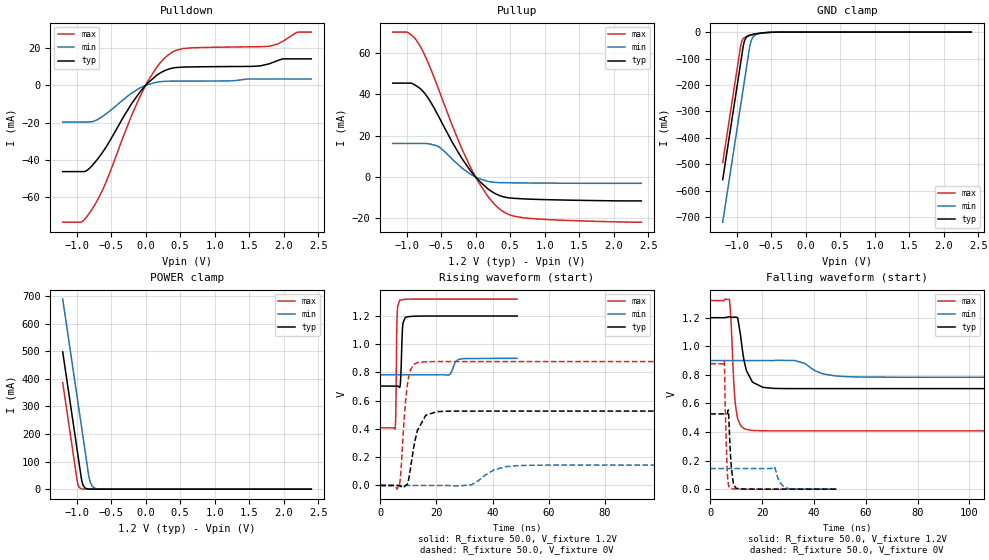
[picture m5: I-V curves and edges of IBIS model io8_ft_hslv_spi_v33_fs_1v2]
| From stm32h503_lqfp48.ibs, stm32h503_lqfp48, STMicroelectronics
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[Model]   io8_ft_hslv_spi_v33_fs_1v2
Model_type I/O
Polarity   Non-Inverting
Enable   Active-Low
| CAP_THRESHOLD on pad IOFT is "UDTCAPC" :
| Rising=20.0% of vddiom   Falling=80.0% of vddiom
| C_comp min and max val. don't necessarily correlate with the min and max pvt
| but are the smallest and greatest pad capacitance found.
| var   typ   min   max
C_comp   3.39570pF  3.37235pF  3.42680pF
|C_comp_pullup   2.09365pF  2.00520pF  1.90825pF
|C_comp_pulldown   1.30205pF  1.36715pF  1.51855pF
Vinl = 270.0mV
Vinh = 924.0mV
Vmeas = 600.0mV   | Reference voltage for timing measurements
Cref  = 50.0pF   | Timing specification test load capacitance value
Rref  = 100.0MOhm   | Timing specification test load resistance value
Vref  = 600.0mV   | Timing specification test load voltage
[Model Spec]
| TIME_THRESHOLD on pin ZIV33M is "CMOS" :
| Rising=40.0% of vddiom   Falling=60.0% of vddiom
Vinl 437.80000mV 335.80000mV 479.80000mV
Vinh 728.20000mV 529.20000mV 807.20000mV
| variable   typ   min   max
[Temperature Range] 25.0 125.0 -40.0
| variable   typ   min   max
[Voltage Range] 1.2V 900.0mV 1.32V
| variable   typ   min   max
[POWER Clamp Reference] 1.2V 900.0mV 1.32V
| variable   typ   min   max
[GND Clamp Reference] 0V 0V 0V
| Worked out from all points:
|   slope of the pulldown table from 0 to 0.18 V, typ, clamps not added: 30.6 ohm
|   slope of the pullup table from 0 to 0.18 V, typ, clamps not added: 31.3 ohm
|   GND clamp passes 1 mA (typ) near -0.52 V on its own axis
|   POWER clamp passes 1 mA (typ) near -0.84 V on its own axis
|   rising waveform, R_fixture 50.0, V_fixture 1.2V: 20-80 % time 520ps typ, 1.45ns min, 319ps max; typ from 0.704 V to 1.2 V
|   falling waveform, R_fixture 50.0, V_fixture 1.2V: 20-80 % time 3.24ns typ, 7.01ns min, 1.6ns max; typ from 1.2 V to 0.704 V
|   rising waveform, R_fixture 50.0, V_fixture 0V: 20-80 % time 3.48ns typ, 6.93ns min, 1.98ns max; typ from 0 V to 0.527 V
|   falling waveform, R_fixture 50.0, V_fixture 0V: 20-80 % time 1.12ns typ, 2.21ns min, 804ps max; typ from 0.527 V to 0 V
[POWER Clamp]
-1.2V     497.8mA    689.2mA    386.5mA
-990mV    140.8mA    332.2mA    29.53mA
-980mV    123.8mA    315.2mA    17.95mA
-960mV    89.81mA    281.2mA    6.634mA
-930mV    38.81mA    230.2mA    1.49mA
-900mV    12.07mA    179.2mA    334.8uA
-870mV    3.756mA    128.2mA    75.22uA
-820mV    536.4uA    44.98mA    6.246uA
-790mV    166.9uA    18.76mA    1.403uA
-750mV    35.18uA    5.846mA    191.8nA
-590mV    70.08nA    55uA       163.4pA
2.4V      0A         0A         0A
[GND Clamp]
-1.2V     -558.2mA   -719mA     -494.1mA
-940mV    -116.2mA   -277mA     -52.06mA
-930mV    -99.19mA   -260mA     -39.94mA
-900mV    -49.1mA    -209mA     -23.76mA
-880mV    -30.14mA   -175mA     -19.6mA
-850mV    -17.82mA   -124mA     -16.09mA
-810mV    -11.73mA   -56.78mA   -12.91mA
-780mV    -9.444mA   -28.21mA   -10.92mA
-740mV    -7.291mA   -13.16mA   -8.574mA
-640mV    -3.573mA   -4.171mA   -3.954mA
-380mV    -61.75uA   -230.3uA   -20.32uA
2.4V      3.863nA    718.6nA    150.6pA
| variable   typ   min   max
[Pullup Reference] 1.2V 900.0mV 1.32V
| variable   typ   min   max
[Pulldown Reference] 0V 0V 0V
[Pullup]
-1.2V     45.41mA    16.23mA    70.08mA
-990mV    45.41mA    16.23mA    70.08mA
-820mV    43.23mA    16.23mA    64.23mA
-700mV    38.81mA    16.16mA    56.25mA
-540mV    29.64mA    14.73mA    42.86mA
-330mV    16.36mA    8.38mA     24.24mA
-80mV     3.305mA    1.499mA    5.124mA
170mV     -5.505mA   -2.032mA   -9.004mA
360mV     -9.115mA   -2.712mA   -15.76mA
540mV     -10.25mA   -2.811mA   -18.8mA
790mV     -10.7mA    -2.892mA   -20.02mA
2.4V      -11.55mA   -3.057mA   -21.84mA
[Pulldown]
-1.2V     -46.17mA   -19.62mA   -73.27mA
-930mV    -46.17mA   -19.62mA   -73.18mA
-770mV    -42.8mA    -19.41mA   -66.04mA
-570mV    -32.88mA   -15.18mA   -51.58mA
-80mV     -3.488mA   -1.363mA   -5.887mA
160mV     5.368mA    1.686mA    9.621mA
340mV     8.782mA    2.251mA    16.66mA
540mV     9.805mA    2.305mA    19.74mA
1.79V     11.53mA    3.428mA    20.94mA
1.98V     14.11mA    3.428mA    23.43mA
2.2V      14.2mA     3.428mA    28.44mA
2.4V      14.2mA     3.428mA    28.54mA
[Ramp]
dV/dt_r 315.97829mV/3.11017ns 86.46871mV/6.5409ns 526.34887mV/1.98266ns
dV/dt_f 297.80503mV/2.96734ns 69.92309mV/6.87924ns 547.13925mV/1.59983ns
R_load = 50.0
| Removed startup time: 0s 0s 0s  .
| Removed end time: 48.75ns.
[Rising Waveform]
R_fixture   = 50.0
V_fixture   = 1.2V
V_fixture_min = 900.0mV
V_fixture_max = 1.32V
0s        703.7mV    783.5mV    408.1mV
5.3ns     703.7mV    783.5mV    404.1mV
5.55ns    703.8mV    783.5mV    536.4mV
5.8ns     703.8mV    783.5mV    1.003V
6ns       703.9mV    783.5mV    1.205V
6.9ns     694.2mV    783.5mV    1.312V
7.3ns     771.8mV    783.5mV    1.312V
8ns       1.133V     783.5mV    1.316V
8.95ns    1.191V     783.5mV    1.318V
48.75ns   1.2V       899.9mV    1.32V
| Removed startup time: 0s 0s 0s  .
| Removed end time: 198.75ns.
[Falling Waveform]
R_fixture   = 50.0
V_fixture   = 1.2V
V_fixture_min = 900.0mV
V_fixture_max = 1.32V
0s        1.2V       900mV      1.32V
7.4ns     1.207V     900mV      1.324V
9.1ns     1.204V     900mV      736.5mV
9.7ns     1.204V     900mV      591.1mV
10.65ns   1.192V     900mV      488.5mV
13.95ns   829.2mV    900mV      417.5mV
16.25ns   749.4mV    900mV      410.7mV
24.35ns   705.5mV    899.6mV    408.1mV
52.75ns   703.7mV    787.3mV    408.1mV
198.8ns   703.7mV    783.5mV    408.1mV
| Removed startup time: 0s 0s 0s  .
| Removed end time: 198.7ns.
[Rising Waveform]
R_fixture   = 50.0
V_fixture   = 0V
V_fixture_min = 0V
V_fixture_max = 0V
0s        198.1nV    697.3nV    135nV
6.8ns     -866.9uV   704.3nV    6.54mV
7.3ns     -7.541mV   702.4nV    86.73mV
8.8ns     -3.423mV   691.5nV    545mV
9.8ns     18.47mV    679.1nV    733.6mV
13.2ns    387.9mV    568.3nV    870mV
20.3ns    523.1mV    793.1nV    877.1mV
32.5ns    526.5mV    4.756mV    877.2mV
48.7ns    526.5mV    140.1mV    877.2mV
198.7ns   526.6mV    144.1mV    877.2mV
| Removed startup time: 0s 0s 0s  .
| Removed end time: 48.75ns.
[Falling Waveform]
R_fixture   = 50.0
V_fixture   = 0V
V_fixture_min = 0V
V_fixture_max = 0V
0s        526.6mV    144.1mV    877.3mV
5.4ns     526.7mV    144.1mV    896.5mV
5.85ns    526.7mV    144.1mV    509.4mV
6.55ns    528.8mV    144.1mV    132.1mV
7.05ns    538.4mV    144.1mV    28.87mV
7.7ns     270.8mV    144.1mV    6.568mV
8.95ns    34.17mV    144.1mV    1.678mV
9.95ns    6.36mV     144.1mV    806.1uV
24.7ns    9.7uV      155.5mV    742.8nV
48.75ns   60.78nV    149.7uV    31.8nV
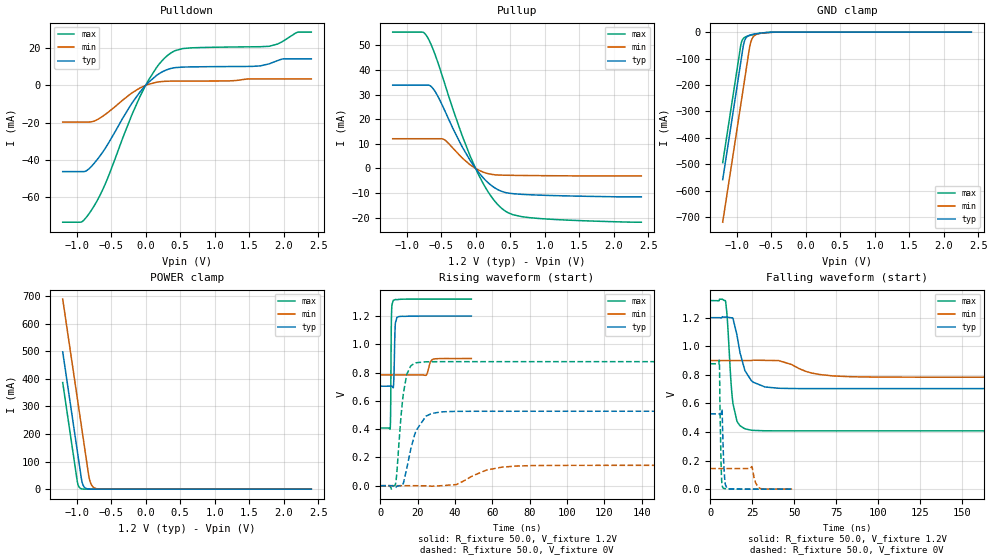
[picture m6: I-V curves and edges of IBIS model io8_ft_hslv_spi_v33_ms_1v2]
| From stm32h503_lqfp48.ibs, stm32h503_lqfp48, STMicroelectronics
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[Model]   io8_ft_hslv_spi_v33_ms_1v2
Model_type I/O
Polarity   Non-Inverting
Enable   Active-Low
| CAP_THRESHOLD on pad IOFT is "UDTCAPC" :
| Rising=20.0% of vddiom   Falling=80.0% of vddiom
| C_comp min and max val. don't necessarily correlate with the min and max pvt
| but are the smallest and greatest pad capacitance found.
| var   typ   min   max
C_comp   3.39570pF  3.37230pF  3.42685pF
|C_comp_pullup   2.09375pF  2.00530pF  1.90840pF
|C_comp_pulldown   1.30195pF  1.36700pF  1.51845pF
Vinl = 270.0mV
Vinh = 924.0mV
Vmeas = 600.0mV   | Reference voltage for timing measurements
Cref  = 50.0pF   | Timing specification test load capacitance value
Rref  = 100.0MOhm   | Timing specification test load resistance value
Vref  = 600.0mV   | Timing specification test load voltage
[Model Spec]
| TIME_THRESHOLD on pin ZIV33M is "CMOS" :
| Rising=40.0% of vddiom   Falling=60.0% of vddiom
Vinl 437.80000mV 335.80000mV 479.80000mV
Vinh 728.20000mV 529.20000mV 807.20000mV
| variable   typ   min   max
[Temperature Range] 25.0 125.0 -40.0
| variable   typ   min   max
[Voltage Range] 1.2V 900.0mV 1.32V
| variable   typ   min   max
[POWER Clamp Reference] 1.2V 900.0mV 1.32V
| variable   typ   min   max
[GND Clamp Reference] 0V 0V 0V
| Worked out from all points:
|   slope of the pulldown table from 0 to 0.18 V, typ, clamps not added: 30.6 ohm
|   slope of the pullup table from 0 to 0.18 V, typ, clamps not added: 31.2 ohm
|   GND clamp passes 1 mA (typ) near -0.52 V on its own axis
|   POWER clamp passes 1 mA (typ) near -0.84 V on its own axis
|   rising waveform, R_fixture 50.0, V_fixture 1.2V: 20-80 % time 520ps typ, 1.44ns min, 319ps max; typ from 0.704 V to 1.2 V
|   falling waveform, R_fixture 50.0, V_fixture 1.2V: 20-80 % time 6.64ns typ, 15.8ns min, 3.24ns max; typ from 1.2 V to 0.704 V
|   rising waveform, R_fixture 50.0, V_fixture 0V: 20-80 % time 6.92ns typ, 14.9ns min, 3.69ns max; typ from 0 V to 0.527 V
|   falling waveform, R_fixture 50.0, V_fixture 0V: 20-80 % time 1.07ns typ, 2.17ns min, 800ps max; typ from 0.527 V to 0 V
[POWER Clamp]
-1.2V     497.8mA    689.2mA    386.5mA
-990mV    140.8mA    332.2mA    29.53mA
-980mV    123.8mA    315.2mA    17.95mA
-960mV    89.81mA    281.2mA    6.634mA
-930mV    38.81mA    230.2mA    1.49mA
-900mV    12.07mA    179.2mA    334.8uA
-870mV    3.756mA    128.2mA    75.22uA
-820mV    536.4uA    44.98mA    6.246uA
-790mV    166.9uA    18.76mA    1.403uA
-750mV    35.18uA    5.846mA    191.8nA
-590mV    70.08nA    55uA       163.4pA
2.4V      0A         0A         0A
[GND Clamp]
-1.2V     -558.2mA   -719mA     -494.1mA
-940mV    -116.2mA   -277mA     -52.06mA
-930mV    -99.19mA   -260mA     -39.94mA
-900mV    -49.1mA    -209mA     -23.76mA
-880mV    -30.14mA   -175mA     -19.6mA
-850mV    -17.82mA   -124mA     -16.09mA
-810mV    -11.73mA   -56.78mA   -12.91mA
-780mV    -9.444mA   -28.21mA   -10.92mA
-740mV    -7.291mA   -13.16mA   -8.574mA
-640mV    -3.573mA   -4.171mA   -3.954mA
-380mV    -61.75uA   -230.3uA   -20.32uA
2.4V      3.863nA    718.6nA    150.6pA
| variable   typ   min   max
[Pullup Reference] 1.2V 900.0mV 1.32V
| variable   typ   min   max
[Pulldown Reference] 0V 0V 0V
[Pullup]
-1.2V     33.83mA    12.07mA    55.39mA
-770mV    33.83mA    12.07mA    55.39mA
-700mV    33.83mA    12.07mA    53.47mA
-600mV    31.84mA    12.07mA    47.27mA
-450mV    23.73mA    11.63mA    34.72mA
-200mV    9.076mA    4.405mA    13.76mA
0V        5.98pA     656pA      2.91pA
200mV     -6.256mA   -2.236mA   -10.31mA
400mV     -9.528mA   -2.741mA   -16.71mA
540mV     -10.25mA   -2.81mA    -18.8mA
790mV     -10.7mA    -2.891mA   -20.02mA
2.4V      -11.55mA   -3.057mA   -21.84mA
[Pulldown]
-1.2V     -46.17mA   -19.62mA   -73.27mA
-930mV    -46.17mA   -19.62mA   -73.18mA
-770mV    -42.8mA    -19.41mA   -66.04mA
-570mV    -32.88mA   -15.18mA   -51.58mA
-80mV     -3.488mA   -1.363mA   -5.887mA
160mV     5.368mA    1.686mA    9.621mA
340mV     8.782mA    2.251mA    16.66mA
540mV     9.805mA    2.305mA    19.74mA
1.79V     11.53mA    3.428mA    20.94mA
1.98V     14.11mA    3.428mA    23.43mA
2.2V      14.2mA     3.428mA    28.44mA
2.4V      14.2mA     3.428mA    28.54mA
[Ramp]
dV/dt_r 315.9766mV/6.30353ns 86.46mV/14.30989ns 526.3497mV/3.54733ns
dV/dt_f 297.8051mV/6.16485ns 69.92056mV/15.0681ns 547.13928mV/3.15941ns
R_load = 50.0
| Removed startup time: 0s 0s 0s  .
| Removed end time: 48.75ns.
[Rising Waveform]
R_fixture   = 50.0
V_fixture   = 1.2V
V_fixture_min = 900.0mV
V_fixture_max = 1.32V
0s        703.7mV    783.5mV    408.1mV
5.3ns     703.7mV    783.5mV    402.5mV
5.55ns    703.7mV    783.5mV    531.4mV
5.85ns    703.7mV    783.5mV    1.067V
6ns       703.8mV    783.5mV    1.205V
6.9ns     692.1mV    783.5mV    1.31V
7.3ns     769.4mV    783.5mV    1.313V
8ns       1.132V     783.5mV    1.316V
8.95ns    1.191V     783.5mV    1.316V
48.75ns   1.2V       899.5mV    1.32V
| Removed startup time: 0s 0s 0s  .
| Removed end time: 398.75ns.
[Falling Waveform]
R_fixture   = 50.0
V_fixture   = 1.2V
V_fixture_min = 900.0mV
V_fixture_max = 1.32V
0s        1.2V       900mV      1.32V
9.05ns    1.204V     900mV      1.317V
10.1ns    1.204V     900mV      1.198V
12.2ns    1.2V       900mV      772.2mV
13.5ns    1.195V     900mV      599.4mV
16.3ns    1.05V      900mV      466.6mV
20.6ns    830mV      900mV      422.2mV
24.4ns    760mV      899.6mV    412.6mV
85.1ns    703.7mV    786.5mV    408.1mV
398.8ns   703.7mV    783.5mV    408.1mV
| Removed startup time: 0s 0s 0s  .
| Removed end time: 398.7ns.
[Rising Waveform]
R_fixture   = 50.0
V_fixture   = 0V
V_fixture_min = 0V
V_fixture_max = 0V
0s        188.3nV    695.1nV    128.8nV
8.1ns     -14.09mV   699.3nV    9.156mV
12.4ns    19.26mV    622.9nV    656mV
14.2ns    123.6mV    487.8nV    788.6mV
19.2ns    390.2mV    758.2nV    869.5mV
27.4ns    510.4mV    -3.642mV   876.9mV
40.7ns    525.8mV    8.138mV    877.1mV
57ns      526.4mV    110.7mV    877.2mV
73.2ns    526.5mV    139.4mV    877.2mV
398.7ns   526.6mV    144.1mV    877.2mV
| Removed startup time: 0s 0s 0s  .
| Removed end time: 48.75ns.
[Falling Waveform]
R_fixture   = 50.0
V_fixture   = 0V
V_fixture_min = 0V
V_fixture_max = 0V
0s        526.6mV    144.1mV    877.3mV
5.4ns     526.7mV    144.1mV    900.4mV
5.85ns    526.7mV    144.1mV    516mV
6.55ns    529.1mV    144.1mV    131.2mV
7.05ns    545.1mV    144.1mV    27.43mV
7.7ns     275.3mV    144.1mV    7.634mV
8.55ns    78.95mV    144.1mV    4.106mV
9.95ns    5.762mV    144.1mV    2.501mV
24.7ns    131.6uV    158.5mV    14.21uV
48.75ns   871.1nV    485.8uV    36.49nV
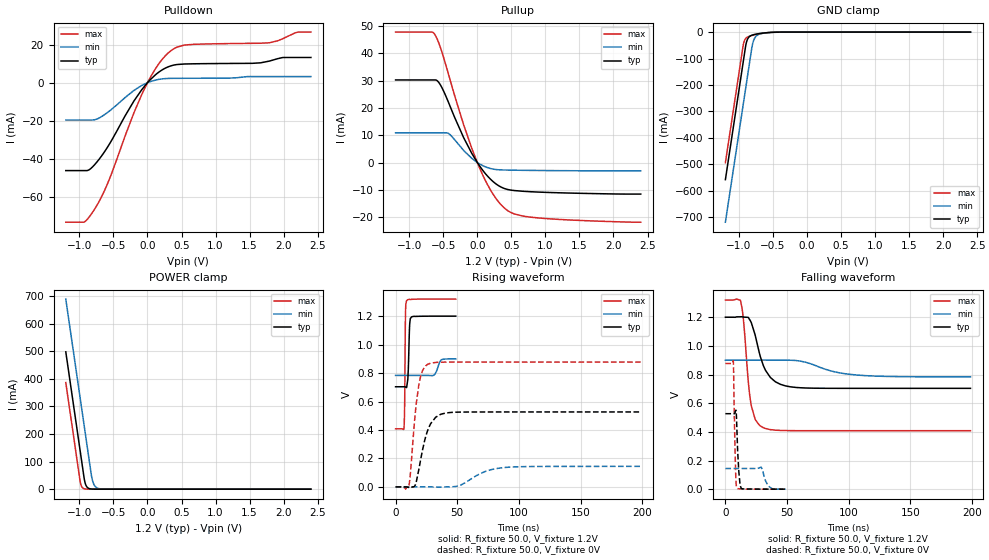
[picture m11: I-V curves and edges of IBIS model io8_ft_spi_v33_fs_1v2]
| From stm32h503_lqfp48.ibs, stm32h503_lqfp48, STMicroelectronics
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[Model]   io8_ft_spi_v33_fs_1v2
Model_type I/O
Polarity   Non-Inverting
Enable   Active-Low
| CAP_THRESHOLD on pad IOFT is "UDTCAPC" :
| Rising=20.0% of vddiom   Falling=80.0% of vddiom
| C_comp min and max val. don't necessarily correlate with the min and max pvt
| but are the smallest and greatest pad capacitance found.
| var   typ   min   max
C_comp   3.39520pF  3.36980pF  3.42665pF
|C_comp_pullup   2.08475pF  1.99620pF  1.90095pF
|C_comp_pulldown   1.31045pF  1.37360pF  1.52570pF
Vinl = 270.0mV
Vinh = 924.0mV
Vmeas = 600.0mV   | Reference voltage for timing measurements
Cref  = 50.0pF   | Timing specification test load capacitance value
Rref  = 100.0MOhm   | Timing specification test load resistance value
Vref  = 600.0mV   | Timing specification test load voltage
[Model Spec]
| TIME_THRESHOLD on pin ZIV33M is "CMOS" :
| Rising=40.0% of vddiom   Falling=60.0% of vddiom
Vinl 437.80000mV 335.80000mV 479.80000mV
Vinh 728.20000mV 529.20000mV 807.20000mV
| variable   typ   min   max
[Temperature Range] 25.0 125.0 -40.0
| variable   typ   min   max
[Voltage Range] 1.2V 900.0mV 1.32V
| variable   typ   min   max
[POWER Clamp Reference] 1.2V 900.0mV 1.32V
| variable   typ   min   max
[GND Clamp Reference] 0V 0V 0V
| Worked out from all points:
|   slope of the pulldown table from 0 to 0.18 V, typ, clamps not added: 30.6 ohm
|   slope of the pullup table from 0 to 0.18 V, typ, clamps not added: 31.2 ohm
|   GND clamp passes 1 mA (typ) near -0.52 V on its own axis
|   POWER clamp passes 1 mA (typ) near -0.84 V on its own axis
|   rising waveform, R_fixture 50.0, V_fixture 1.2V: 20-80 % time 1.03ns typ, 2.95ns min, 542ps max; typ from 0.704 V to 1.2 V
|   falling waveform, R_fixture 50.0, V_fixture 1.2V: 20-80 % time 11.4ns typ, 27.5ns min, 5.74ns max; typ from 1.2 V to 0.704 V
|   rising waveform, R_fixture 50.0, V_fixture 0V: 20-80 % time 8.75ns typ, 18.9ns min, 5.83ns max; typ from 0 V to 0.527 V
|   falling waveform, R_fixture 50.0, V_fixture 0V: 20-80 % time 1.76ns typ, 3.89ns min, 1.26ns max; typ from 0.527 V to 0 V
[POWER Clamp]
-1.2V     497.8mA    689.2mA    386.5mA
-990mV    140.8mA    332.2mA    29.53mA
-980mV    123.8mA    315.2mA    17.95mA
-960mV    89.81mA    281.2mA    6.634mA
-930mV    38.81mA    230.2mA    1.49mA
-900mV    12.07mA    179.2mA    334.8uA
-870mV    3.756mA    128.2mA    75.22uA
-820mV    536.4uA    44.98mA    6.246uA
-790mV    166.9uA    18.76mA    1.403uA
-750mV    35.18uA    5.846mA    191.8nA
-590mV    70.09nA    55uA       165.5pA
2.4V      0A         0A         0A
[GND Clamp]
-1.2V     -558.2mA   -719mA     -494.1mA
-940mV    -116.2mA   -277mA     -52.06mA
-930mV    -99.19mA   -260mA     -39.94mA
-900mV    -49.1mA    -209mA     -23.76mA
-880mV    -30.14mA   -175mA     -19.6mA
-850mV    -17.82mA   -124mA     -16.09mA
-810mV    -11.73mA   -56.78mA   -12.91mA
-780mV    -9.444mA   -28.21mA   -10.92mA
-740mV    -7.291mA   -13.16mA   -8.574mA
-640mV    -3.573mA   -4.171mA   -3.954mA
-380mV    -61.75uA   -230.3uA   -20.32uA
2.4V      3.863nA    718.4nA    150.6pA
| variable   typ   min   max
[Pullup Reference] 1.2V 900.0mV 1.32V
| variable   typ   min   max
[Pulldown Reference] 0V 0V 0V
[Pullup]
-1.2V     30.2mA     10.86mA    47.72mA
-660mV    30.2mA     10.86mA    47.71mA
-620mV    30.2mA     10.86mA    46.69mA
-540mV    28.32mA    10.86mA    41.96mA
-420mV    21.81mA    10.57mA    32.02mA
-200mV    9.076mA    4.404mA    13.76mA
0V        5.98pA     656pA      2.91pA
220mV     -6.72mA    -2.348mA   -11.13mA
420mV     -9.693mA   -2.753mA   -17.12mA
540mV     -10.25mA   -2.811mA   -18.8mA
900mV     -10.82mA   -2.919mA   -20.3mA
2.4V      -11.55mA   -3.057mA   -21.84mA
[Pulldown]
-1.2V     -46.17mA   -19.62mA   -73.27mA
-930mV    -46.17mA   -19.62mA   -73.18mA
-770mV    -42.8mA    -19.41mA   -66.04mA
-570mV    -32.88mA   -15.18mA   -51.58mA
-200mV    -9.658mA   -4.083mA   -15.89mA
-80mV     -3.488mA   -1.363mA   -5.887mA
120mV     4.232mA    1.387mA    7.501mA
340mV     8.782mA    2.251mA    16.66mA
540mV     9.805mA    2.305mA    19.74mA
1.79V     11.33mA    3.206mA    20.93mA
2.2V      13.23mA    3.206mA    26.48mA
2.4V      13.23mA    3.206mA    26.56mA
[Ramp]
dV/dt_r 315.94699mV/8.63249ns 86.40379mV/18.62437ns 526.33866mV/5.7566ns
dV/dt_f 297.80515mV/10.97974ns 69.86081mV/27.41264ns 547.1393mV/5.72596ns
R_load = 50.0
| Removed startup time: 0s 0s 0s  .
| Removed end time: 48.75ns.
[Rising Waveform]
R_fixture   = 50.0
V_fixture   = 1.2V
V_fixture_min = 900.0mV
V_fixture_max = 1.32V
0s        703.7mV    783.5mV    408.1mV
6.85ns    703.8mV    783.5mV    419.2mV
7.35ns    703.8mV    783.5mV    580.7mV
8.05ns    701.8mV    783.5mV    1.221V
8.95ns    697.9mV    783.5mV    1.31V
9.95ns    759.1mV    783.5mV    1.316V
11.25ns   1.11V      783.5mV    1.318V
11.95ns   1.183V     783.5mV    1.317V
30.85ns   1.2V       784mV      1.32V
48.75ns   1.2V       899.4mV    1.32V
| Removed startup time: 0s 0s 0s  .
| Removed end time: 198.75ns.
[Falling Waveform]
R_fixture   = 50.0
V_fixture   = 1.2V
V_fixture_min = 900.0mV
V_fixture_max = 1.32V
0s        1.2V       900mV      1.32V
12.2ns    1.203V     900mV      1.317V
14.6ns    1.201V     900mV      1.184V
18.75ns   1.196V     900mV      734.7mV
21.05ns   1.161V     900mV      580.2mV
30.85ns   860.9mV    901.2mV    428.7mV
40.55ns   749.4mV    900.9mV    411.8mV
56.8ns    710.3mV    898.3mV    408.3mV
105.5ns   703.7mV    797.4mV    408.1mV
198.8ns   703.7mV    783.6mV    408.1mV
| Removed startup time: 0s 0s 0s  .
| Removed end time: 198.7ns.
[Rising Waveform]
R_fixture   = 50.0
V_fixture   = 0V
V_fixture_min = 0V
V_fixture_max = 0V
0s        198.4nV    700.8nV    136.1nV
10.8ns    -4.237mV   698nV      10.63mV
15.8ns    10.14mV    944.2nV    503.2mV
18.9ns    124.3mV    945.6nV    721.1mV
21.8ns    257.5mV    76.39nV    816.8mV
26.5ns    408.2mV    39.29uV    863.3mV
32.5ns    489.5mV    -1.143mV   874.7mV
44.6ns    523mV      133.9uV    877mV
85.2ns    526.4mV    133.2mV    877.2mV
198.7ns   526.6mV    144mV      877.2mV
| Removed startup time: 0s 0s 0s  .
| Removed end time: 48.75ns.
[Falling Waveform]
R_fixture   = 50.0
V_fixture   = 0V
V_fixture_min = 0V
V_fixture_max = 0V
0s        526.7mV    144.2mV    877.3mV
6.4ns     526.4mV    144.2mV    893.8mV
7.95ns    536.7mV    144.2mV    228.3mV
8.7ns     544.7mV    144.2mV    41.58mV
9.35ns    411.8mV    144.2mV    8.883mV
10.95ns   116.7mV    144.2mV    2.415mV
12.95ns   4.583mV    144.2mV    1.802mV
28.9ns    287.3uV    153.5mV    62.31uV
35.85ns   122.9uV    15.13mV    17.65uV
48.75ns   25.84uV    364.1uV    1.61uV
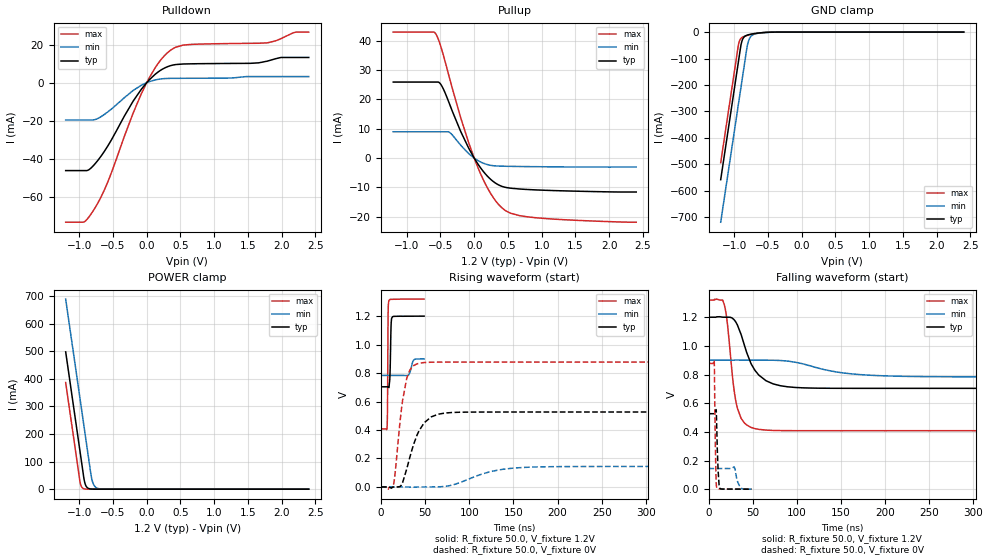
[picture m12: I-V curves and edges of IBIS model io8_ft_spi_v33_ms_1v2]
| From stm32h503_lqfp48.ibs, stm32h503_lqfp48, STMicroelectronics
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[Model]   io8_ft_spi_v33_ms_1v2
Model_type I/O
Polarity   Non-Inverting
Enable   Active-Low
| CAP_THRESHOLD on pad IOFT is "UDTCAPC" :
| Rising=20.0% of vddiom   Falling=80.0% of vddiom
| C_comp min and max val. don't necessarily correlate with the min and max pvt
| but are the smallest and greatest pad capacitance found.
| var   typ   min   max
C_comp   3.39520pF  3.36985pF  3.42675pF
|C_comp_pullup   2.08500pF  1.99655pF  1.90125pF
|C_comp_pulldown   1.31020pF  1.37330pF  1.52550pF
Vinl = 270.0mV
Vinh = 924.0mV
Vmeas = 600.0mV   | Reference voltage for timing measurements
Cref  = 50.0pF   | Timing specification test load capacitance value
Rref  = 100.0MOhm   | Timing specification test load resistance value
Vref  = 600.0mV   | Timing specification test load voltage
[Model Spec]
| TIME_THRESHOLD on pin ZIV33M is "CMOS" :
| Rising=40.0% of vddiom   Falling=60.0% of vddiom
Vinl 437.80000mV 335.80000mV 479.80000mV
Vinh 728.20000mV 529.20000mV 807.20000mV
| variable   typ   min   max
[Temperature Range] 25.0 125.0 -40.0
| variable   typ   min   max
[Voltage Range] 1.2V 900.0mV 1.32V
| variable   typ   min   max
[POWER Clamp Reference] 1.2V 900.0mV 1.32V
| variable   typ   min   max
[GND Clamp Reference] 0V 0V 0V
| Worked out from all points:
|   slope of the pulldown table from 0 to 0.18 V, typ, clamps not added: 30.6 ohm
|   slope of the pullup table from 0 to 0.18 V, typ, clamps not added: 31.2 ohm
|   GND clamp passes 1 mA (typ) near -0.52 V on its own axis
|   POWER clamp passes 1 mA (typ) near -0.84 V on its own axis
|   rising waveform, R_fixture 50.0, V_fixture 1.2V: 20-80 % time 1.02ns typ, 2.94ns min, 538ps max; typ from 0.704 V to 1.2 V
|   falling waveform, R_fixture 50.0, V_fixture 1.2V: 20-80 % time 20.5ns typ, 53.4ns min, 10.1ns max; typ from 1.2 V to 0.704 V
|   rising waveform, R_fixture 50.0, V_fixture 0V: 20-80 % time 17.7ns typ, 41.3ns min, 10.1ns max; typ from 0 V to 0.527 V
|   falling waveform, R_fixture 50.0, V_fixture 0V: 20-80 % time 1.78ns typ, 3.91ns min, 1.26ns max; typ from 0.527 V to 0 V
[POWER Clamp]
-1.2V     497.8mA    689.2mA    386.5mA
-990mV    140.8mA    332.2mA    29.53mA
-980mV    123.8mA    315.2mA    17.95mA
-960mV    89.81mA    281.2mA    6.634mA
-930mV    38.81mA    230.2mA    1.49mA
-900mV    12.07mA    179.2mA    334.8uA
-870mV    3.756mA    128.2mA    75.22uA
-820mV    536.4uA    44.98mA    6.246uA
-790mV    166.9uA    18.76mA    1.403uA
-750mV    35.18uA    5.846mA    191.8nA
-590mV    70.09nA    55uA       165.5pA
2.4V      0A         0A         0A
[GND Clamp]
-1.2V     -558.2mA   -719mA     -494.1mA
-940mV    -116.2mA   -277mA     -52.06mA
-930mV    -99.19mA   -260mA     -39.94mA
-900mV    -49.1mA    -209mA     -23.76mA
-880mV    -30.14mA   -175mA     -19.6mA
-850mV    -17.82mA   -124mA     -16.09mA
-810mV    -11.73mA   -56.78mA   -12.91mA
-780mV    -9.444mA   -28.21mA   -10.92mA
-740mV    -7.291mA   -13.16mA   -8.574mA
-640mV    -3.573mA   -4.171mA   -3.954mA
-380mV    -61.75uA   -230.3uA   -20.32uA
2.4V      3.863nA    718.4nA    150.6pA
| variable   typ   min   max
[Pullup Reference] 1.2V 900.0mV 1.32V
| variable   typ   min   max
[Pulldown Reference] 0V 0V 0V
[Pullup]
-1.2V     25.92mA    8.979mA    42.95mA
-570mV    25.92mA    8.979mA    42.38mA
-490mV    24.97mA    8.979mA    37.69mA
-360mV    18.12mA    8.684mA    26.8mA
-200mV    9.076mA    4.398mA    13.76mA
0V        5.98pA     656pA      2.91pA
220mV     -6.72mA    -2.348mA   -11.13mA
330mV     -8.727mA   -2.679mA   -14.93mA
440mV     -9.832mA   -2.764mA   -17.49mA
670mV     -10.53mA   -2.857mA   -19.6mA
900mV     -10.82mA   -2.918mA   -20.3mA
2.4V      -11.55mA   -3.057mA   -21.84mA
[Pulldown]
-1.2V     -46.17mA   -19.62mA   -73.27mA
-930mV    -46.17mA   -19.62mA   -73.18mA
-770mV    -42.8mA    -19.41mA   -66.04mA
-570mV    -32.88mA   -15.18mA   -51.58mA
-200mV    -9.658mA   -4.083mA   -15.89mA
-80mV     -3.488mA   -1.363mA   -5.887mA
120mV     4.232mA    1.387mA    7.501mA
340mV     8.782mA    2.251mA    16.66mA
540mV     9.805mA    2.305mA    19.74mA
1.79V     11.33mA    3.206mA    20.93mA
2.2V      13.23mA    3.206mA    26.48mA
2.4V      13.23mA    3.206mA    26.56mA
[Ramp]
dV/dt_r 315.94724mV/17.23711ns 86.39956mV/41.17625ns 526.34203mV/9.64308ns
dV/dt_f 297.80513mV/20.1921ns 69.89985mV/53.26832ns 547.1393mV/10.02414ns
R_load = 50.0
| Removed startup time: 0s 0s 0s  .
| Removed end time: 48.75ns.
[Rising Waveform]
R_fixture   = 50.0
V_fixture   = 1.2V
V_fixture_min = 900.0mV
V_fixture_max = 1.32V
0s        703.7mV    783.5mV    408.1mV
6.85ns    703.8mV    783.5mV    418.9mV
7.35ns    703.8mV    783.5mV    577.8mV
8.05ns    701.7mV    783.5mV    1.222V
8.95ns    697.4mV    783.5mV    1.311V
9.95ns    758.4mV    783.5mV    1.317V
11.25ns   1.109V     783.5mV    1.318V
11.95ns   1.184V     783.5mV    1.318V
30.85ns   1.2V       783.9mV    1.32V
48.75ns   1.2V       899.5mV    1.32V
| Removed startup time: 0s 0s 0s  .
| Removed end time: 398.75ns.
[Falling Waveform]
R_fixture   = 50.0
V_fixture   = 1.2V
V_fixture_min = 900.0mV
V_fixture_max = 1.32V
0s        1.2V       900mV      1.32V
17.75ns   1.2V       900mV      1.289V
21.2ns    1.2V       900mV      1.163V
28.7ns    1.184V     900mV      701.8mV
32.55ns   1.148V     901mV      567.6mV
48.85ns   867.8mV    900mV      429.5mV
65.1ns    756.7mV    900mV      412.1mV
97.65ns   710.1mV    886.7mV    408.3mV
179.1ns   703.7mV    796.5mV    408.1mV
398.8ns   703.7mV    783.5mV    408.1mV
| Removed startup time: 0s 0s 0s  .
| Removed end time: 398.7ns.
[Rising Waveform]
R_fixture   = 50.0
V_fixture   = 0V
V_fixture_min = 0V
V_fixture_max = 0V
0s        198nV      700.8nV    136.2nV
14.1ns    -553.2uV   674.9nV    16.09mV
16ns      -471.2uV   972.9nV    100mV
23.3ns    15.78mV    -864.2nV   555.4mV
29.1ns    126.3mV    15.69uV    763.4mV
40.7ns    363.2mV    -467.4uV   864.8mV
57ns      492.8mV    154.9uV    876.4mV
73.2ns    519.7mV    3.865mV    877mV
154.6ns   526.4mV    134.4mV    877.2mV
398.7ns   526.6mV    144mV      877.2mV
| Removed startup time: 0s 0s 0s  .
| Removed end time: 48.75ns.
[Falling Waveform]
R_fixture   = 50.0
V_fixture   = 0V
V_fixture_min = 0V
V_fixture_max = 0V
0s        526.7mV    144.1mV    877.3mV
6.4ns     526.4mV    144.1mV    896.1mV
7.95ns    538mV      144.1mV    232.7mV
8.7ns     549mV      144.1mV    42.68mV
9.35ns    415.7mV    144.1mV    8.371mV
10.95ns   119.5mV    144.1mV    1.728mV
12.95ns   4.313mV    144.1mV    1.097mV
28.9ns    519uV      155.4mV    215.5uV
35.85ns   337.9uV    15.49mV    101uV
48.75ns   129.1uV    274.7uV    26.56uV
